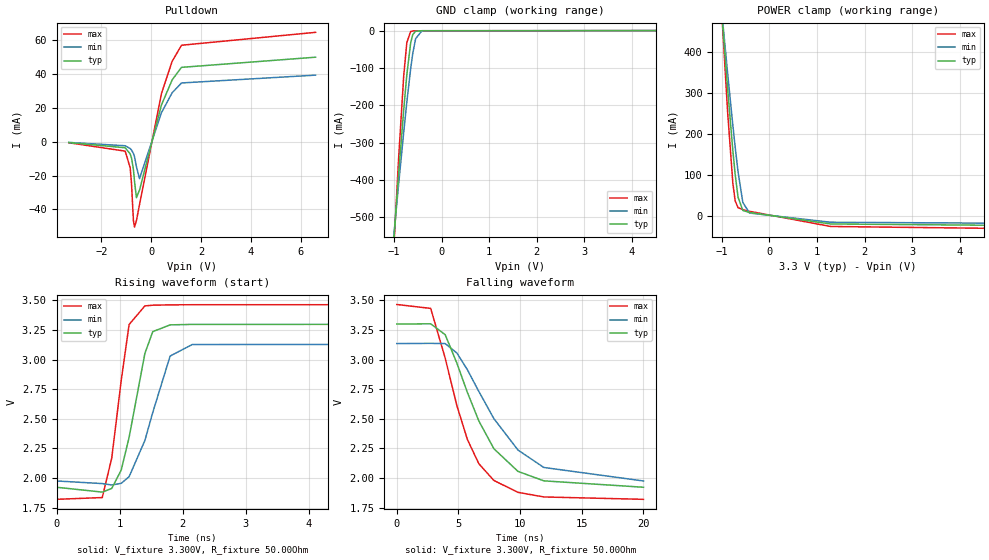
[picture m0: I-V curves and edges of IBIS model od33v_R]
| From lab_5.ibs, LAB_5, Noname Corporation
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[Model]   od33v_R
Model_type   I/O_open_sink
Vinl = 800.000mV
Vinh = 2.000V
Vmeas = 1.400V
Vref = 1.400V
Cref = 5.000pF
Rref = 100.000Ohm
|   typ   min   max
C_comp   4.550pF   2.600pF   6.500pF
[Voltage Range]   3.300V   3.135V   3.465V
[Temperature Range]   50.0   100.0   0.0
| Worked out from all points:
|   slope of the pulldown table from 0 to 0.495 V, typ, clamps not added: 19.8 ohm
|   GND clamp passes 1 mA (typ) near -0.51 V on its own axis
|   falling waveform, V_fixture 3.300V, R_fixture 50.00Ohm: 20-80 % time 3.54ns typ, 4.34ns min, 2.85ns max; typ from 3.3 V to 1.92 V
|   rising waveform, V_fixture 3.300V, R_fixture 50.00Ohm: 20-80 % time 297ps typ, 375ps min, 229ps max; typ from 1.92 V to 3.3 V
[Pulldown]
|   Voltage   I(typ)   I(min)   I(max)
-3.3V     -512.7uA   -417.8uA   -623.6uA
-1.04V    -3.573mA   -2.39mA    -5.568mA
-840mV    -7.178mA   -4.036mA   -15.39mA
-785mV    -9.647mA   -4.934mA   -25.04mA
-710mV    -16.35mA   -6.941mA   -46.45mA
-665mV    -23.45mA   -8.943mA   -50.47mA
-590mV    -33.06mA   -14.69mA   -46.66mA
-465mV    -28.62mA   -21.83mA   -37.2mA
415mV     21.69mA    17.14mA    28.39mA
845mV     36.53mA    28.91mA    47.51mA
1.22V     43.92mA    34.7mA     56.98mA
6.6V      49.92mA    39.32mA    64.61mA
[GND Clamp]
|   Voltage   I(typ)   I(min)   I(max)
-3.3V     -4.836A    -3.871A    -6.575A
-1.14V    -800.6mA   -737.6mA   -916.4mA
-1.095V   -720.2mA   -674.9mA   -804.2mA
-1.065V   -666.9mA   -633.3mA   -730mA
-900mV    -381.2mA   -408.9mA   -337.1mA
-795mV    -211.8mA   -272.2mA   -121.1mA
-730mV    -118.6mA   -192.2mA   -32.33mA
-650mV    -33.67mA   -103.1mA   -2.727mA
-605mV    -10.79mA   -61.25mA   -1.187mA
-545mV    -2.021mA   -21.89mA   -864.6uA
-415mV    -515.1uA   -979.7uA   -643.1uA
6.6V      0A         0A         0A
[POWER Clamp]
|   Voltage   I(typ)   I(min)   I(max)
-3.3V     4.234A     3.486A     5.484A
-1.145V   714mA      674mA      783mA
-1.1V     643.7mA    617.7mA    689.6mA
-1.06V    581.6mA    567.8mA    607.3mA
-880mV    310.9mA    348.5mA    254.5mA
-770mV    160.1mA    221.6mA    80.84mA
-720mV    100.8mA    167.5mA    37.04mA
-660mV    46.33mA    107.7mA    20.9mA
-560mV    14.16mA    33.74mA    16.28mA
-420mV    9.277mA    7.886mA    12.15mA
1.285V    -18.69mA   -14.53mA   -24.81mA
6.6V      -23.7mA    -18.04mA   -32.03mA
[Ramp]
R_load = 50.00Ohm
|   typ   min   max
dV/dt_r   826.602mV/297.343ps 695.704mV/375.127ps 986.866mV/229.499ps
dV/dt_f   826.602mV/3.544ns   695.704mV/4.335ns   986.866mV/2.846ns
[Falling Waveform]
V_fixture = 3.300V
V_fixture_min = 3.135V
V_fixture_max = 3.465V
R_fixture = 50.00Ohm
|   Time   V(typ)   V(min)   V(max)
0s        3.3V       3.135V     3.465V
2.75ns    3.302V     3.137V     3.432V
3.925ns   3.21V      3.135V     3.012V
4.875ns   2.969V     3.055V     2.61V
5.725ns   2.722V     2.914V     2.325V
6.65ns    2.482V     2.731V     2.121V
7.875ns   2.247V     2.501V     1.979V
9.825ns   2.056V     2.236V     1.879V
11.92ns   1.976V     2.089V     1.84V
20ns      1.922V     1.975V     1.82V
[Rising Waveform]
V_fixture = 3.300V
V_fixture_min = 3.135V
V_fixture_max = 3.465V
R_fixture = 50.00Ohm
|   Time   V(typ)   V(min)   V(max)
0s        1.922V     1.975V     1.82V
725ps     1.881V     1.953V     1.835V
875ps     1.912V     1.941V     2.169V
1.025ns   2.067V     1.955V     2.823V
1.15ns    2.343V     2.011V     3.296V
1.4ns     3.052V     2.317V     3.453V
1.525ns   3.236V     2.554V     3.459V
1.8ns     3.293V     3.03V      3.462V
2.15ns    3.297V     3.127V     3.463V
20ns      3.3V       3.135V     3.465V
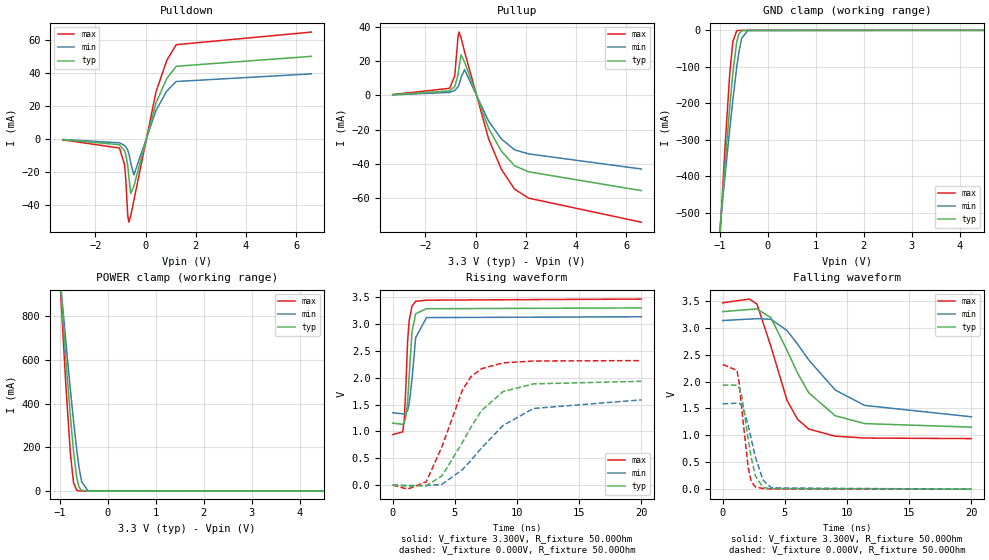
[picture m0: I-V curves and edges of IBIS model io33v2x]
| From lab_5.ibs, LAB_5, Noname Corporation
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[Model]   io33v2x
Model_type   I/O
Vinl = 800.000mV
Vinh = 2.000V
Vmeas = 1.400V
Cref = 0.000F
|   typ   min   max
C_comp   4.550pF   2.600pF   6.500pF
[Voltage Range]   3.300V   3.135V   3.465V
[Temperature Range]   50.0   100.0   0.0
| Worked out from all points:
|   slope of the pulldown table from 0 to 0.495 V, typ, clamps not added: 19.8 ohm
|   slope of the pullup table from 0 to 0.495 V, typ, clamps not added: 26.9 ohm
|   GND clamp passes 1 mA (typ) near -0.54 V on its own axis
|   POWER clamp passes 1 mA (typ) near -0.52 V on its own axis
|   falling waveform, V_fixture 3.300V, R_fixture 50.00Ohm: 20-80 % time 3.11ns typ, 4.19ns min, 2.1ns max; typ from 3.3 V to 1.15 V
|   rising waveform, V_fixture 3.300V, R_fixture 50.00Ohm: 20-80 % time 351ps typ, 425ps min, 293ps max; typ from 1.15 V to 3.3 V
|   rising waveform, V_fixture 0.000V, R_fixture 50.00Ohm: 20-80 % time 3.12ns typ, 4.08ns min, 2.24ns max; typ from 0 V to 1.93 V
|   falling waveform, V_fixture 0.000V, R_fixture 50.00Ohm: 20-80 % time 797ps typ, 994ps min, 622ps max; typ from 1.93 V to 0 V
[Pulldown]
|   Voltage   I(typ)   I(min)   I(max)
-3.3V     -512.7uA   -417.8uA   -623.6uA
-1.04V    -3.573mA   -2.39mA    -5.568mA
-840mV    -7.179mA   -4.036mA   -15.39mA
-785mV    -9.647mA   -4.934mA   -25.04mA
-710mV    -16.35mA   -6.941mA   -46.44mA
-665mV    -23.45mA   -8.943mA   -50.47mA
-590mV    -33.06mA   -14.69mA   -46.66mA
-465mV    -28.62mA   -21.83mA   -37.2mA
415mV     21.68mA    17.14mA    28.39mA
845mV     36.53mA    28.91mA    47.51mA
1.22V     43.92mA    34.7mA     56.98mA
6.6V      49.92mA    39.32mA    64.61mA
[GND Clamp]
|   Voltage   I(typ)   I(min)   I(max)
-3.3V     -4.831A    -3.868A    -6.57A
-1.14V    -799.2mA   -736.5mA   -914.7mA
-1.095V   -718.9mA   -673.8mA   -802.5mA
-1.065V   -665.6mA   -632.3mA   -728.4mA
-900mV    -380.1mA   -408mA     -335.7mA
-795mV    -210.9mA   -271.4mA   -119.9mA
-730mV    -117.7mA   -191.5mA   -31.21mA
-650mV    -32.88mA   -102.5mA   -1.72mA
-605mV    -10.06mA   -60.66mA   -249.3uA
-545mV    -1.362mA   -21.37mA   -19.52uA
-415mV    -13.11uA   -577.7uA   -79.94nA
6.6V      0A         0A         0A
[Pullup]
|   Voltage   I(typ)   I(min)   I(max)
-3.3V     372.9uA    298.9uA    463.9uA
-1.03V    2.584mA    1.702mA    4.113mA
-830mV    5.172mA    2.868mA    11.29mA
-700mV    11.75mA    4.926mA    34.15mA
-660mV    16.23mA    6.156mA    36.87mA
-580mV    23.64mA    10.42mA    33.64mA
-440mV    19.42mA    14.94mA    25.46mA
520mV     -19.23mA   -15.07mA   -25.41mA
1.025V    -32.51mA   -25.36mA   -43.06mA
1.55V     -41.02mA   -31.74mA   -54.62mA
2.105V    -44.55mA   -34.1mA    -59.9mA
6.6V      -55.54mA   -42.94mA   -73.94mA
[POWER Clamp]
|   Voltage   I(typ)   I(min)   I(max)
-3.3V     8.467A     6.971A     10.97A
-1.115V   1.332A     1.271A     1.438A
-1.09V    1.254A     1.209A     1.334A
-1.05V    1.13A      1.109A     1.17A
-875mV    603.1mA    682.7mA    482.5mA
-780mV    339mA      462.1mA    169mA
-715mV    180.4mA    319.9mA    37.46mA
-650mV    62.19mA    190.5mA    3.276mA
-600mV    16.81mA    106.7mA    402.4uA
-545mV    2.714mA    41.25mA    39.02uA
-415mV    26.21uA    1.154mA    155.4nA
6.6V      0A         0A         0A
[Ramp]
R_load = 50.00Ohm
|   typ   min   max
dV/dt_r   1.160V/3.118ns   951.944mV/4.081ns   1.391V/2.239ns
dV/dt_f   1.288V/3.111ns   1.073V/4.187ns   1.515V/2.099ns
[Falling Waveform]
V_fixture = 3.300V
V_fixture_min = 3.135V
V_fixture_max = 3.465V
R_fixture = 50.00Ohm
|   Time   V(typ)   V(min)   V(max)
0s        3.3V       3.135V     3.465V
2.15ns    3.34V      3.162V     3.534V
2.75ns    3.352V     3.17V      3.443V
3.875ns   3.187V     3.158V     2.656V
5.175ns   2.579V     2.95V      1.651V
6.025ns   2.157V     2.694V     1.297V
6.925ns   1.791V     2.401V     1.118V
9.05ns    1.365V     1.843V     984.8mV
11.42ns   1.219V     1.557V     950.6mV
20ns      1.153V     1.346V     940mV
[Rising Waveform]
V_fixture = 3.300V
V_fixture_min = 3.135V
V_fixture_max = 3.465V
R_fixture = 50.00Ohm
|   Time   V(typ)   V(min)   V(max)
0s        1.153V     1.346V     940mV
800ps     1.131V     1.326V     989.9mV
925ps     1.161V     1.32V      1.199V
1.05ns    1.255V     1.332V     1.789V
1.2ns     1.554V     1.393V     2.682V
1.325ns   2.027V     1.512V     3.062V
1.55ns    2.851V     1.966V     3.332V
1.85ns    3.192V     2.749V     3.423V
2.725ns   3.285V     3.12V      3.445V
20ns      3.3V       3.135V     3.465V
[Rising Waveform]
V_fixture = 0.000V
V_fixture_min = 0.000V
V_fixture_max = 0.000V
R_fixture = 50.00Ohm
|   Time   V(typ)   V(min)   V(max)
0s        251.9nV    309.9nV    317nV
1.2ns     -19.62mV   -6.613mV   -76.84mV
2.7ns     -12.55mV   -9.282mV   61.47mV
3.95ns    167.2mV    12.06mV    708.1mV
5.6ns     789.3mV    284.9mV    1.764V
6.275ns   1.071V     454mV      2.014V
7.15ns    1.39V      691.5mV    2.168V
8.875ns   1.741V     1.11V      2.276V
11.33ns   1.885V     1.427V     2.311V
20ns      1.933V     1.587V     2.318V
[Falling Waveform]
V_fixture = 0.000V
V_fixture_min = 0.000V
V_fixture_max = 0.000V
R_fixture = 50.00Ohm
|   Time   V(typ)   V(min)   V(max)
0s        1.933V     1.587V     2.318V
1.15ns    1.936V     1.597V     2.207V
1.325ns   1.886V     1.596V     1.977V
1.55ns    1.71V      1.562V     1.449V
2.05ns    934.1mV    1.2V       400mV
2.3ns     581.9mV    925.4mV    139.6mV
2.625ns   247.4mV    600.9mV    42.69mV
3.25ns    30.25mV    166.4mV    10.78mV
3.925ns   11.34mV    22.45mV    4.918mV
20ns      251.9nV    309.9nV    317nV
